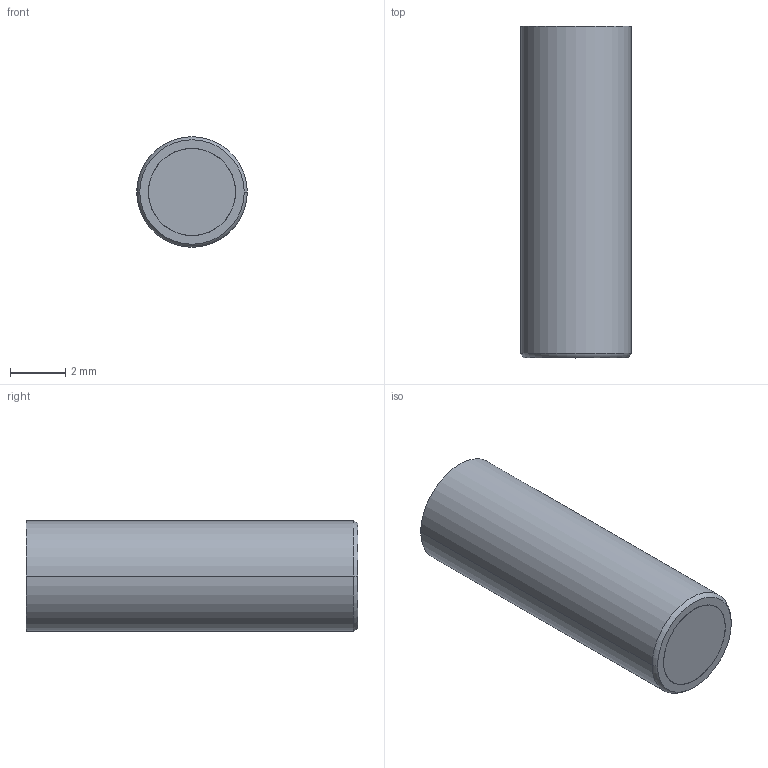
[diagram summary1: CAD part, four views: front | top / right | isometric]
STEP (ISO 10303-21) file: header records copied from the file, then geometry measured from it (millimetres).
FILE_DESCRIPTION (( 'STEP AP214' ), '1' );
FILE_NAME ('FA 042204-21.STEP', '2020-08-10T10:50:44', ( '' ), ( '' ), 'SwSTEP 2.0', 'SolidWorks 2019', '' );
FILE_SCHEMA (( 'AUTOMOTIVE_DESIGN' ));
Length unit declared in the file: millimetre
Products named in the file (6): FA 042200-2; FA 042200-1; FA 042204-21; IA 2275SF; FA 042204-14-1; FA 042200-3
Assembly tree (5 placements, depth 2):
  FA 042204-21
    FA 042204-14-1
    IA 2275SF
    FA 042200-3
    FA 042200-2
    FA 042200-1
Bounding box: 4 x 12 x 4 mm (x, y, z)
Volume: 123.2 mm3; surface area: 462 mm2
Topology: 5 solids, 5 shells, 194 faces, 477 edges, 311 vertices
Faces by surface type: plane 78, bspline 63, cylinder 37, cone 14, torus 2
Entity records: 9861 total; most frequent: CARTESIAN_POINT 5298, ORIENTED_EDGE 950, DIRECTION 721, EDGE_CURVE 475, VERTEX_POINT 311, VECTOR 257, LINE 257, AXIS2_PLACEMENT_3D 232
One B-rep face of a CAD part: STEP entity #2520.
In plain terms, the planar face has unit normal (-1, 0, 0).
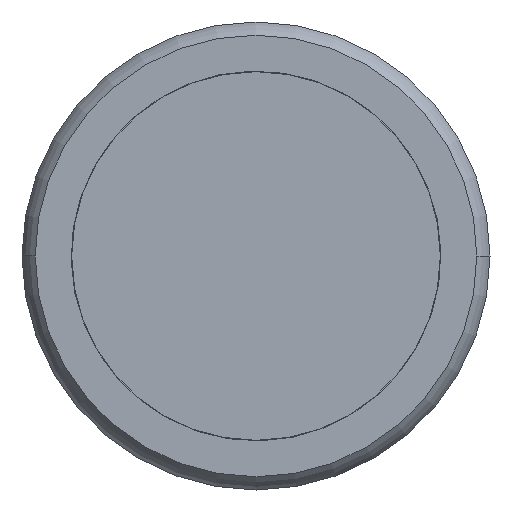
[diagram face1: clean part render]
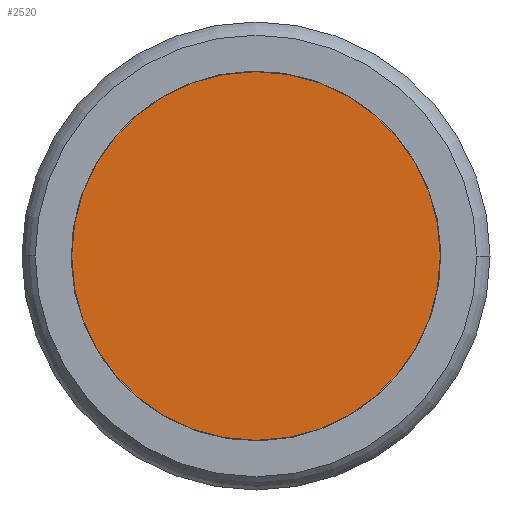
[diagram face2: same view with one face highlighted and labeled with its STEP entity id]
Its self-contained STEP definition (entity closure, numbers rounded to 3 decimals):
#135 = DIRECTION ( 'NONE',  ( 1., 0., 0. ) ) ;
#720 = AXIS2_PLACEMENT_3D ( 'NONE', #829, #8466, #6946 ) ;
#829 = CARTESIAN_POINT ( 'NONE',  ( 0.374, 1.735, -10. ) ) ;
#914 = ORIENTED_EDGE ( 'NONE', *, *, #7824, .F. ) ;
#1728 = AXIS2_PLACEMENT_3D ( 'NONE', #9157, #4513, #8289 ) ;
#2520 = ADVANCED_FACE ( 'NONE', ( #3932 ), #7705, .F. ) ;
#2749 = VERTEX_POINT ( 'NONE', #6635 ) ;
#3121 = VERTEX_POINT ( 'NONE', #7079 ) ;
#3852 = DIRECTION ( 'NONE',  ( 0., 1., 0. ) ) ;
#3932 = FACE_OUTER_BOUND ( 'NONE', #5676, .T. ) ;
#4428 = ORIENTED_EDGE ( 'NONE', *, *, #5029, .F. ) ;
#4513 = DIRECTION ( 'NONE',  ( 1., 0., 0. ) ) ;
#4908 = CIRCLE ( 'NONE', #7471, 1.58 ) ;
#5029 = EDGE_CURVE ( 'NONE', #3121, #2749, #4908, .T. ) ;
#5676 = EDGE_LOOP ( 'NONE', ( #4428, #914 ) ) ;
#6635 = CARTESIAN_POINT ( 'NONE',  ( 0.374, 0., -1.58 ) ) ;
#6946 = DIRECTION ( 'NONE',  ( 0., 1., 0. ) ) ;
#7079 = CARTESIAN_POINT ( 'NONE',  ( 0.374, 0., 1.58 ) ) ;
#7471 = AXIS2_PLACEMENT_3D ( 'NONE', #9956, #135, #3852 ) ;
#7661 = CIRCLE ( 'NONE', #1728, 1.58 ) ;
#7705 = PLANE ( 'NONE',  #720 ) ;
#7824 = EDGE_CURVE ( 'NONE', #2749, #3121, #7661, .T. ) ;
#8289 = DIRECTION ( 'NONE',  ( 0., 1., 0. ) ) ;
#8466 = DIRECTION ( 'NONE',  ( 1., 0., 0. ) ) ;
#9157 = CARTESIAN_POINT ( 'NONE',  ( 0.374, 0., 0. ) ) ;
#9956 = CARTESIAN_POINT ( 'NONE',  ( 0.374, 0., 0. ) ) ;
